VERSION 5.8 ;
BUSBITCHARS "[]" ;
DIVIDERCHAR "/" ;
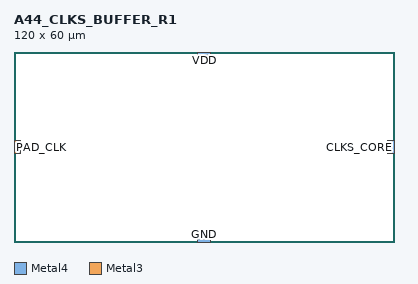
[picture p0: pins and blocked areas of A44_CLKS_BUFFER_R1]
MACRO A44_CLKS_BUFFER_R1
  CLASS BLOCK ;
  ORIGIN 0 0 ;
  FOREIGN A44_CLKS_BUFFER_R1 0 0 ;
  SIZE 120 BY 60 ;
  SYMMETRY X Y ;
  SITE CoreSite ;
  PIN VDD
    DIRECTION INOUT ;
    USE POWER ;
    PORT
      LAYER Metal4 ;
        RECT 58 58 62 60 ;
    END
  END VDD
  PIN GND
    DIRECTION INOUT ;
    USE GROUND ;
    PORT
      LAYER Metal4 ;
        RECT 58 0 62 2 ;
    END
  END GND
  PIN CLKS_CORE
    DIRECTION OUTPUT ;
    USE SIGNAL ;
    PORT
      LAYER Metal4 ;
        RECT 118 28 120 32 ;
    END
  END CLKS_CORE
  PIN PAD_CLK
    DIRECTION INPUT ;
    USE SIGNAL ;
    PORT
      LAYER Metal3 ;
        RECT 0 28 2 32 ;
    END
  END PAD_CLK
END A44_CLKS_BUFFER_R1
END LIBRARY
